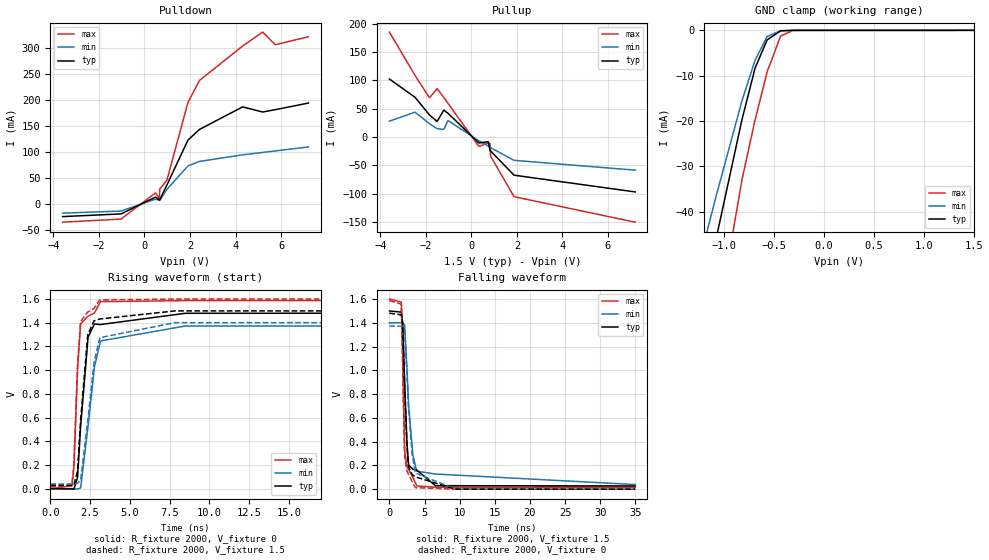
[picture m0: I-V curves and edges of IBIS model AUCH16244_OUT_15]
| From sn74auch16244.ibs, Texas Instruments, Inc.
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[Model]   AUCH16244_OUT_15
Model_type  3-state
Enable   Active-Low
Vref =   0
Rref =   2000
Cref =   15p
Vmeas =   0.75
| variable   typ   min   max
C_comp   5.56pF   4.98pF   5.81pF
| C_pullup   4.87pF   0.16pF   12.46pF
| C_pulldown   6.28pF   5.37pF   9.81pF
| C_tri-state   5.56pF   4.98pF   5.81pF
[Temperature Range]   40   100   -40
| Ambient temperature   25   85   -40
[Voltage range]   1.5   1.4   1.6
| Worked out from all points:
|   slope of the pulldown table from 0 to 0.225 V, typ, clamps not added: 37.2 ohm
|   slope of the pullup table from 0 to 0.225 V, typ, clamps not added: 30 ohm
|   GND clamp passes 1 mA (typ) near -0.53 V on its own axis
|   rising waveform, R_fixture 2000, V_fixture 0: 20-80 % time 448ps typ, 645ps min, 290ps max; typ from 0 V to 1.48 V
|   falling waveform, R_fixture 2000, V_fixture 1.5: 20-80 % time 548ps typ, 871ps min, 327ps max; typ from 1.5 V to 0.027 V
|   rising waveform, R_fixture 2000, V_fixture 1.5: 20-80 % time 445ps typ, 647ps min, 288ps max; typ from 0.027 V to 1.5 V
|   falling waveform, R_fixture 2000, V_fixture 0: 20-80 % time 547ps typ, 868ps min, 317ps max; typ from 1.48 V to 0 V
[GND Clamp]
| AUCH16244_OUT_15
|   Voltage   I(typ)   I(min)   I(max)
-3.6V     -322.9mA   -271.3mA   -392.8mA
-1.475V   -88.59mA   -71.54mA   -117.9mA
-1.34V    -73.92mA   -59.41mA   -100.2mA
-1.3V     -69.59mA   -55.85mA   -94.97mA
-1.135V   -51.9mA    -41.38mA   -73.31mA
-1.085V   -46.6mA    -37.08mA   -66.75mA
-820mV    -19.61mA   -15.47mA   -32.88mA
-690mV    -8.335mA   -6.605mA   -19.75mA
-570mV    -2.107mA   -1.378mA   -9.166mA
-435mV    -119.4uA   -67.96uA   -1.249mA
-310mV    -3.104uA   -3.774uA   -25uA
1.5V      550.3pA    9.378nA    545.2pA
[Pulldown]
| AUCH16244_OUT_15
|   Voltage   I(typ)   I(min)   I(max)
-3.6V     -23.87mA   -17.26mA   -34.61mA
-1.03V    -18.71mA   -13.15mA   -28.63mA
485mV     13.68mA    9.737mA    21.72mA
660mV     8.179mA    6.953mA    10.96mA
670mV     8.319mA    7.1mA      28.79mA
985mV     36.88mA    28.41mA    46.12mA
1.91V     123.2mA    73.57mA    195.6mA
2.415V    143.6mA    82.17mA    237.7mA
4.315V    187mA      94.84mA    304mA
5.195V    177.1mA    99.4mA     330.7mA
5.745V    181.6mA    102.3mA    306.4mA
7.2V      194.3mA    110mA      321.7mA
[Pullup]
| AUCH16244_OUT_15
|   Voltage   I(typ)   I(min)   I(max)
-3.6V     102.1mA    27.92mA    184.9mA
-2.475V   70.01mA    43.77mA    108.5mA
-1.84V    38.84mA    23.47mA    69.11mA
-1.505V   27.39mA    14.66mA    85.19mA
-1.21V    47.39mA    13.5mA     69.72mA
-1.025V   41.71mA    29.01mA    59.25mA
330mV     -10.46mA   -6.758mA   -16.68mA
740mV     -8.272mA   -15.76mA   -10.25mA
820mV     -23.65mA   -18mA      -11.49mA
845mV     -24.61mA   -18.86mA   -33.67mA
1.875V    -67.28mA   -41.09mA   -105.2mA
7.2V      -96.75mA   -58.41mA   -150.1mA
[Ramp]
| AUCH16244_OUT_15
| variable   typ   min   max
dV/dt_r   0.89/4.68E-10   0.83/6.51E-10   0.96/3.05E-10
dV/dt_f   0.88/5.66E-10   0.82/9.04E-10   0.95/3.59E-10
R_load = 2000
[Rising Waveform]
| AUCH16244_OUT_15
R_fixture =   2000
C_fixture =   0
L_fixture =   0
V_fixture =   0
V_fixture_min = 0
V_fixture_max = 0
|   Time   V(typ)   V(min)   V(max)
0s        8.895nV    33.88nV    950.2pV
1.37ns    -2.946mV   -1.597mV   23.33mV
1.485ns   -4.462mV   -2.996mV   178.2mV
1.715ns   96.58mV    -2.288mV   1.016V
1.905ns   523.4mV    5.774mV    1.39V
2.375ns   1.28V      529mV      1.456V
2.775ns   1.39V      1.027V     1.482V
3.15ns    1.385V     1.246V     1.578V
8.49ns    1.48V      1.373V     1.587V
34.99ns   1.481V     1.373V     1.587V
[Falling Waveform]
| AUCH16244_OUT_15
R_fixture =   2000
C_fixture =   0
L_fixture =   0
V_fixture =   1.5
V_fixture_min = 1.4
V_fixture_max = 1.6
|   Time   V(typ)   V(min)   V(max)
0s        1.5V       1.4V       1.6V
1.695ns   1.49V      1.401V     1.574V
1.89ns    1.401V     1.399V     1.109V
2.165ns   891.1mV    1.381V     324.2mV
2.5ns     382.6mV    1.003V     189.2mV
2.735ns   202.7mV    701.5mV    163.6mV
3.34ns    167.3mV    284.5mV    99.17mV
3.885ns   160.9mV    151.6mV    27.09mV
6.55ns    29.31mV    127.4mV    16.58mV
34.99ns   27.21mV    38.76mV    16.42mV
[Rising Waveform]
| AUCH16244_OUT_15
R_fixture =   2000
C_fixture =   0
L_fixture =   0
V_fixture =   1.5
V_fixture_min = 1.4
V_fixture_max = 1.6
|   Time   V(typ)   V(min)   V(max)
0s        27.17mV    38.75mV    16.4mV
1.345ns   27.17mV    38.26mV    26.77mV
1.48ns    27.29mV    37.69mV    198.8mV
1.715ns   150.5mV    46.01mV    1.052V
1.905ns   578.2mV    70.84mV    1.41V
2.355ns   1.299V     574.9mV    1.491V
2.75ns    1.417V     1.063V     1.521V
3.11ns    1.432V     1.274V     1.593V
7.83ns    1.5V       1.401V     1.6V
34.99ns   1.5V       1.4V       1.6V
[Falling Waveform]
| AUCH16244_OUT_15
R_fixture =   2000
C_fixture =   0
L_fixture =   0
V_fixture =   0
V_fixture_min = 0
V_fixture_max = 0
|   Time   V(typ)   V(min)   V(max)
0s        1.481V     1.373V     1.587V
1.695ns   1.467V     1.371V     1.557V
1.885ns   1.381V     1.367V     1.011V
2.165ns   870.7mV    1.341V     274.7mV
2.48ns    376.1mV    986.7mV    158.3mV
2.695ns   193.4mV    703mV      127.4mV
3.23ns    122.6mV    298.9mV    63.37mV
3.69ns    103.8mV    136.4mV    12.91mV
9.315ns   295.9uV    2.599mV    99.35uV
34.99ns   41.59uV    6.536uV    17.46uV
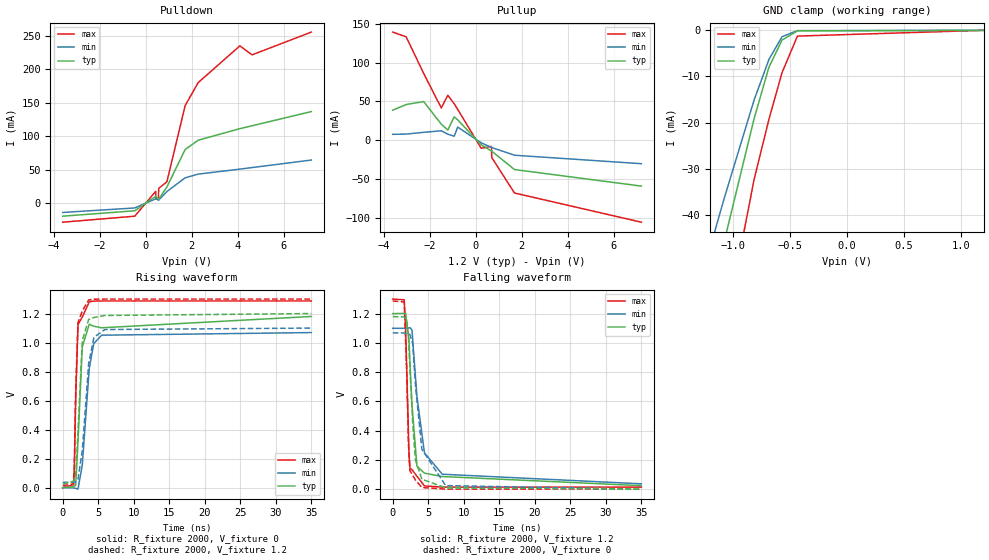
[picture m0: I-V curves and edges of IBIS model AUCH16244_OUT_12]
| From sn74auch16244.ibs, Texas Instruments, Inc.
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[Model]   AUCH16244_OUT_12
Model_type  3-state
Enable   Active-Low
Vref =   0
Rref =   2000
Cref =   15p
Vmeas =   0.6
| variable   typ   min   max
C_comp   5.67pF   5.13pF   5.90pF
| C_pullup   4.93pF   0.60pF   9.68pF
| C_pulldown   6.26pF   5.49pF   7.46pF
| C_tri-state   5.67pF   5.13pF   5.90pF
[Temperature Range]   40   100   -40
| Ambient temperature   25   85   -40
[Voltage range]   1.2   1.1   1.3
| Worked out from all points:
|   slope of the pulldown table from 0 to 0.18 V, typ, clamps not added: 42.1 ohm
|   slope of the pullup table from 0 to 0.18 V, typ, clamps not added: 38.3 ohm
|   GND clamp passes 1 mA (typ) near -0.53 V on its own axis
|   rising waveform, R_fixture 2000, V_fixture 0: 20-80 % time 619ps typ, 992ps min, 358ps max; typ from 0 V to 1.18 V
|   falling waveform, R_fixture 2000, V_fixture 1.2: 20-80 % time 815ps typ, 1.38ns min, 411ps max; typ from 1.2 V to 0.024 V
|   rising waveform, R_fixture 2000, V_fixture 1.2: 20-80 % time 626ps typ, 988ps min, 357ps max; typ from 0.024 V to 1.2 V
|   falling waveform, R_fixture 2000, V_fixture 0: 20-80 % time 804ps typ, 1.31ns min, 404ps max; typ from 1.18 V to 0 V
[GND Clamp]
| AUCH16244_OUT_12
|   Voltage   I(typ)   I(min)   I(max)
-3.6V     -322.9mA   -271.3mA   -392.8mA
-1.47V    -88.05mA   -71.09mA   -117.3mA
-1.425V   -83.15mA   -67.03mA   -111.4mA
-1.3V     -69.59mA   -55.85mA   -94.97mA
-1.26V    -65.27mA   -52.31mA   -89.72mA
-1.11V    -49.24mA   -39.22mA   -70.03mA
-1.075V   -45.55mA   -36.22mA   -65.44mA
-815mV    -19.13mA   -15.09mA   -32.31mA
-685mV    -7.975mA   -6.314mA   -19.28mA
-570mV    -2.107mA   -1.378mA   -9.166mA
-435mV    -119.4uA   -67.96uA   -1.249mA
1.2V      442.5pA    9.259nA    389.9pA
[Pulldown]
| AUCH16244_OUT_12
|   Voltage   I(typ)   I(min)   I(max)
-3.6V     -19.18mA   -13.63mA   -28.17mA
-470mV    -11.13mA   -6.91mA    -19.23mA
440mV     10.48mA    6.706mA    17.92mA
445mV     10.59mA    6.769mA    6.318mA
560mV     5.857mA    4.698mA    8.209mA
570mV     5.97mA     4.786mA    22.41mA
925mV     24.38mA    17.54mA    32.09mA
1.72V     80.36mA    38.11mA    146mA
2.285V    94.25mA    43.63mA    180.3mA
4.095V    111.5mA    51.07mA    235.1mA
4.625V    115.8mA    53.41mA    221.7mA
7.2V      137mA      64.62mA    255.7mA
[Pullup]
| AUCH16244_OUT_12
|   Voltage   I(typ)   I(min)   I(max)
-3.6V     38.61mA    7.555mA    139.2mA
-3.015V   45.91mA    7.851mA    133.1mA
-2.255V   49.73mA    10.14mA    86.01mA
-1.49V    20.68mA    12.09mA    41.55mA
-1.205V   13.08mA    7.704mA    57.86mA
-930mV    30.05mA    5.088mA    46.93mA
-775mV    26.1mA     16.83mA    39.5mA
245mV     -5.916mA   -3.381mA   -10.43mA
690mV     -14.05mA   -9.319mA   -7.997mA
705mV     -14.25mA   -9.473mA   -22.45mA
1.69V     -37.81mA   -19.38mA   -68.01mA
7.2V      -59.11mA   -30.28mA   -105.6mA
[Ramp]
| AUCH16244_OUT_12
| variable   typ   min   max
dV/dt_r   0.71/6.25E-10   0.65/1.03E-09   0.78/3.75E-10
dV/dt_f   0.71/8.54E-10   0.64/1.42E-09   0.77/4.16E-10
R_load = 2000
[Rising Waveform]
| AUCH16244_OUT_12
R_fixture =   2000
C_fixture =   0
L_fixture =   0
V_fixture =   0
V_fixture_min = 0
V_fixture_max = 0
|   Time   V(typ)   V(min)   V(max)
0s        8.336nV    36nV       765.5pV
1.53ns    7.096mV    -1.597mV   20.26mV
1.635ns   10.3mV     -2.554mV   125.6mV
1.83ns    17.67mV    -4.752mV   624.2mV
2.155ns   323.6mV    -10.15mV   1.124V
2.755ns   971.3mV    156.1mV    1.176V
3.735ns   1.126V     820.6mV    1.281V
4.365ns   1.113V     992.8mV    1.286V
5.48ns    1.102V     1.051V     1.287V
34.99ns   1.18V      1.069V     1.287V
[Falling Waveform]
| AUCH16244_OUT_12
R_fixture =   2000
C_fixture =   0
L_fixture =   0
V_fixture =   1.2
V_fixture_min = 1.1
V_fixture_max = 1.3
|   Time   V(typ)   V(min)   V(max)
0s        1.2V       1.1V       1.3V
1.62ns    1.202V     1.1V       1.295V
1.82ns    1.203V     1.1V       1.1V
2.295ns   1.012V     1.103V     236.6mV
2.44ns    847.3mV    1.104V     139.1mV
2.715ns   576mV      1.087V     133.3mV
3.41ns    156.8mV    634.3mV    88.49mV
4.47ns    109.6mV    247.9mV    22.2mV
6.975ns   86.39mV    102.2mV    14.07mV
34.99ns   24.03mV    36.64mV    13.88mV
[Rising Waveform]
| AUCH16244_OUT_12
R_fixture =   2000
C_fixture =   0
L_fixture =   0
V_fixture =   1.2
V_fixture_min = 1.1
V_fixture_max = 1.3
|   Time   V(typ)   V(min)   V(max)
0s        23.98mV    36.61mV    13.86mV
1.485ns   44.32mV    37.78mV    26.42mV
1.62ns    57.97mV    38.49mV    129.2mV
1.835ns   87.44mV    40.04mV    670.7mV
2.145ns   380.7mV    55.91mV    1.137V
2.76ns    1.015V     259.4mV    1.218V
3.655ns   1.159V     854.6mV    1.294V
4.4ns     1.173V     1.036V     1.299V
5.94ns    1.187V     1.09V      1.3V
34.99ns   1.2V       1.1V       1.3V
[Falling Waveform]
| AUCH16244_OUT_12
R_fixture =   2000
C_fixture =   0
L_fixture =   0
V_fixture =   0
V_fixture_min = 0
V_fixture_max = 0
|   Time   V(typ)   V(min)   V(max)
0s        1.18V      1.069V     1.287V
1.615ns   1.178V     1.068V     1.28V
1.96ns    1.149V     1.067V     821.7mV
2.22ns    1.042V     1.062V     304.4mV
2.415ns   839.9mV    1.058V     127.3mV
2.82ns    445.1mV    993.2mV    95.46mV
3.2ns     199.6mV    711.4mV    62.14mV
4.105ns   68.09mV    272.8mV    11.14mV
7.455ns   8.817mV    24.34mV    178.9uV
34.99ns   51.13uV    18.56uV    19.4uV
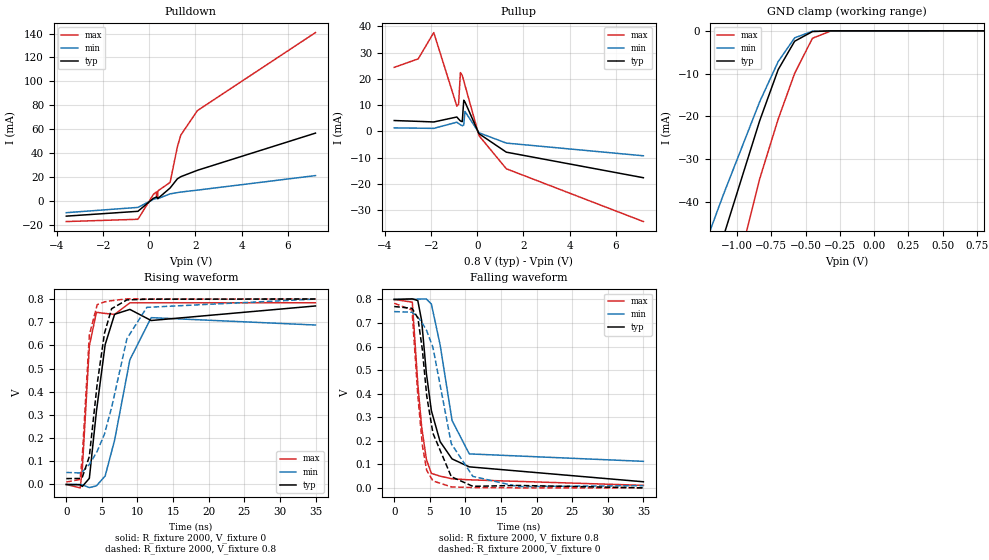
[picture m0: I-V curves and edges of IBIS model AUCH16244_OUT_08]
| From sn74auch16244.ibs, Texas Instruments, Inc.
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[Model]   AUCH16244_OUT_08
Model_type  3-state
Enable   Active-Low
Vref =   0
Rref =   2000
Cref =   15p
Vmeas =   0.4
| variable   typ   min   max
C_comp   5.77pF   5.27pF   6.02pF
| C_pullup   5.89pF   1.41pF   8.23pF
| C_pulldown   6.39pF   5.81pF   6.84pF
| C_tri-state   5.77pF   5.27pF   6.02pF
[Temperature Range]   40   100   -40
| Ambient temperature   25   85   -40
[Voltage range]   0.8   0.8   0.8
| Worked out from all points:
|   slope of the pulldown table from 0 to 0.12 V, typ, clamps not added: 77.5 ohm
|   slope of the pullup table from 0 to 0.12 V, typ, clamps not added: 92.7 ohm
|   GND clamp passes 1 mA (typ) near -0.53 V on its own axis
|   rising waveform, R_fixture 2000, V_fixture 0: 20-80 % time 1.8ns typ, 2.59ns min, 926ps max; typ from 0 V to 0.77 V
|   falling waveform, R_fixture 2000, V_fixture 0.8: 20-80 % time 2.64ns typ, 2.31ns min, 1.37ns max; typ from 0.8 V to 0.026 V
|   rising waveform, R_fixture 2000, V_fixture 0.8: 20-80 % time 1.84ns typ, 3.62ns min, 893ps max; typ from 0.025 V to 0.8 V
|   falling waveform, R_fixture 2000, V_fixture 0: 20-80 % time 2.27ns typ, 2.98ns min, 1.24ns max; typ from 0.77 V to 0 V
[GND Clamp]
| AUCH16244_OUT_08
|   Voltage   I(typ)   I(min)   I(max)
-3.6V     -322.9mA   -271.3mA   -392.8mA
-1.495V   -90.78mA   -73.35mA   -120.5mA
-1.455V   -86.41mA   -69.74mA   -115.3mA
-1.31V    -70.67mA   -56.74mA   -96.28mA
-1.14V    -52.43mA   -41.81mA   -73.96mA
-1.1V     -48.18mA   -38.36mA   -68.71mA
-835mV    -21.05mA   -16.6mA    -34.66mA
-700mV    -9.08mA    -7.201mA   -20.67mA
-580mV    -2.442mA   -1.648mA   -9.983mA
-450mV    -176.5uA   -96.06uA   -1.735mA
-315mV    -3.617uA   -4.295uA   -30.24uA
800mV     320.2pA    582.4pA    244.4pA
[Pulldown]
| AUCH16244_OUT_08
|   Voltage   I(typ)   I(min)   I(max)
-3.6V     -12.84mA   -9.953mA   -17.38mA
-495mV    -8.803mA   -5.523mA   -15.47mA
175mV     2.059mA    1.185mA    5.31mA
310mV     3.174mA    2.053mA    7.502mA
315mV     3.217mA    2.087mA    2.47mA
365mV     1.856mA    1.796mA    2.807mA
370mV     1.894mA    1.829mA    8.27mA
900mV     10.72mA    5.829mA    15.4mA
1.215V    18.4mA     6.852mA    45.18mA
1.365V    20.2mA     7.318mA    55.07mA
2.085V    25.54mA    8.939mA    75.52mA
7.2V      56.65mA    21.1mA     140.8mA
[Pullup]
| AUCH16244_OUT_08
|   Voltage   I(typ)   I(min)   I(max)
-3.6V     4.13mA     1.333mA    24.36mA
-2.56V    3.817mA    1.227mA    27.6mA
-1.885V   3.587mA    1.149mA    37.6mA
-885mV    5.478mA    3.491mA    9.6mA
-810mV    4.708mA    3.016mA    10.3mA
-730mV    3.982mA    2.544mA    22.37mA
-650mV    3.702mA    2.149mA    21.3mA
-585mV    11.85mA    2.417mA    19.32mA
-535mV    11.24mA    7.608mA    17.64mA
75mV      -881.4uA   -518.8uA   -1.613mA
1.26V     -7.908mA   -4.45mA    -14.23mA
7.2V      -17.63mA   -9.285mA   -34.31mA
[Ramp]
| AUCH16244_OUT_08
| variable   typ   min   max
dV/dt_r   0.47/1.86E-09   0.46/3.13E-09   0.48/9.74E-10
dV/dt_f   0.47/2.73E-09   0.42/2.37E-09   0.47/1.38E-09
R_load = 2000
[Rising Waveform]
| AUCH16244_OUT_08
R_fixture =   2000
C_fixture =   0
L_fixture =   0
V_fixture =   0
V_fixture_min = 0
V_fixture_max = 0
|   Time   V(typ)   V(min)   V(max)
0s        10.26nV    58.84nV    576.2pV
1.96ns    -1.273mV   181.3uV    -14.48mV
2.26ns    -8.298mV   -1.661mV   72.03mV
3.24ns    26.71mV    -13.46mV   598mV
4.23ns    314.7mV    -5.935mV   742.6mV
5.46ns    603.3mV    36.89mV    737.7mV
6.785ns   734mV      191mV      733.6mV
8.93ns    755mV      538.1mV    783.3mV
11.92ns   707.2mV    719.5mV    783.5mV
34.99ns   769.9mV    687.7mV    783.7mV
[Falling Waveform]
| AUCH16244_OUT_08
R_fixture =   2000
C_fixture =   0
L_fixture =   0
V_fixture =   0.8
V_fixture_min = 0.8
V_fixture_max = 0.8
|   Time   V(typ)   V(min)   V(max)
0s        800mV      800mV      800mV
2.545ns   802.5mV    800.4mV    788.5mV
3.315ns   795.2mV    801.4mV    440.6mV
3.855ns   709.4mV    802mV      258.8mV
4.515ns   486.9mV    801.9mV    121.4mV
5.22ns    327.7mV    780.6mV    61.41mV
6.445ns   196.4mV    607.7mV    49.72mV
8.125ns   122.9mV    286.1mV    38.4mV
10.54ns   89.24mV    144.2mV    34.08mV
34.99ns   25.83mV    112.6mV    10.63mV
[Rising Waveform]
| AUCH16244_OUT_08
R_fixture =   2000
C_fixture =   0
L_fixture =   0
V_fixture =   0.8
V_fixture_min = 0.8
V_fixture_max = 0.8
|   Time   V(typ)   V(min)   V(max)
0s        25.46mV    51.93mV    10.6mV
1.94ns    26.05mV    49.77mV    21.91mV
2.245ns   30.82mV    54.01mV    118.9mV
3.235ns   120.5mV    86.31mV    643.5mV
4.335ns   432.6mV    142.6mV    775.2mV
5.36ns    651.9mV    217.4mV    787.6mV
6.365ns   758.1mV    331.8mV    792.8mV
8.52ns    796.1mV    629.2mV    800.5mV
11.31ns   799mV      763.9mV    799.8mV
34.99ns   799.9mV    799.6mV    800mV
[Falling Waveform]
| AUCH16244_OUT_08
R_fixture =   2000
C_fixture =   0
L_fixture =   0
V_fixture =   0
V_fixture_min = 0
V_fixture_max = 0
|   Time   V(typ)   V(min)   V(max)
0s        770mV      748.6mV    783.8mV
2.505ns   762.5mV    745.6mV    755mV
3.33ns    720.7mV    724.4mV    386.8mV
3.96ns    585mV      699mV      179.6mV
4.565ns   390.7mV    667.2mV    74.42mV
5.44ns    231.7mV    596.2mV    29.47mV
8.02ns    47.29mV    187.4mV    4.147mV
11.05ns   6.474mV    48.66mV    1.175mV
17.41ns   10.17mV    5.347mV    80.64uV
34.99ns   138uV      9.423mV    29.24uV
